VERSION 5.7 ;
  NOWIREEXTENSIONATPIN ON ;
  DIVIDERCHAR "/" ;
  BUSBITCHARS "[]" ;
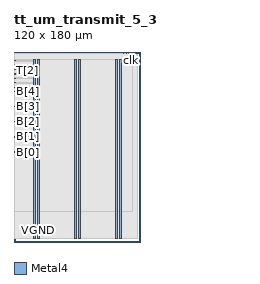
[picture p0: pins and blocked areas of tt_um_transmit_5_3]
MACRO tt_um_transmit_5_3
  CLASS BLOCK ;
  FOREIGN tt_um_transmit_5_3 ;
  ORIGIN 0.000 0.000 ;
  SIZE 120.000 BY 180.000 ;
  PIN B[0]
    DIRECTION OUTPUT ;
    USE SIGNAL ;
    ANTENNADIFFAREA 5.801400 ;
    PORT
      LAYER Metal4 ;
        RECT 0.000 85.100 1.000 85.400 ;
    END
  END B[0]
  PIN B[1]
    DIRECTION OUTPUT ;
    USE SIGNAL ;
    ANTENNADIFFAREA 1.601600 ;
    PORT
      LAYER Metal4 ;
        RECT 0.000 99.400 1.000 99.700 ;
    END
  END B[1]
  PIN B[2]
    DIRECTION OUTPUT ;
    USE SIGNAL ;
    ANTENNADIFFAREA 5.179600 ;
    PORT
      LAYER Metal4 ;
        RECT 0.000 113.700 1.000 114.000 ;
    END
  END B[2]
  PIN B[3]
    DIRECTION OUTPUT ;
    USE SIGNAL ;
    ANTENNADIFFAREA 2.243600 ;
    PORT
      LAYER Metal4 ;
        RECT 0.000 128.000 1.000 128.300 ;
    END
  END B[3]
  PIN B[4]
    DIRECTION OUTPUT ;
    USE SIGNAL ;
    ANTENNADIFFAREA 5.801400 ;
    PORT
      LAYER Metal4 ;
        RECT 0.000 142.300 1.000 142.600 ;
    END
  END B[4]
  PIN T[0]
    DIRECTION OUTPUT ;
    USE SIGNAL ;
    ANTENNADIFFAREA 1.055600 ;
    PORT
      LAYER Metal4 ;
        RECT 0.000 146.500 1.000 146.800 ;
    END
  END T[0]
  PIN T[1]
    DIRECTION OUTPUT ;
    USE SIGNAL ;
    ANTENNADIFFAREA 4.408000 ;
    PORT
      LAYER Metal4 ;
        RECT 0.000 150.700 1.000 151.000 ;
    END
  END T[1]
  PIN T[2]
    DIRECTION OUTPUT ;
    USE SIGNAL ;
    ANTENNADIFFAREA 4.731200 ;
    PORT
      LAYER Metal4 ;
        RECT 0.000 154.900 1.000 155.200 ;
    END
  END T[2]
  PIN T[3]
    DIRECTION OUTPUT ;
    USE SIGNAL ;
    ANTENNADIFFAREA 2.059200 ;
    PORT
      LAYER Metal4 ;
        RECT 0.000 159.100 1.000 159.400 ;
    END
  END T[3]
  PIN T[4]
    DIRECTION OUTPUT ;
    USE SIGNAL ;
    ANTENNAGATEAREA 5.072000 ;
    ANTENNADIFFAREA 3.240100 ;
    PORT
      LAYER Metal4 ;
        RECT 0.000 163.300 1.000 163.600 ;
    END
  END T[4]
  PIN T[5]
    DIRECTION OUTPUT ;
    USE SIGNAL ;
    ANTENNADIFFAREA 4.731200 ;
    PORT
      LAYER Metal4 ;
        RECT 0.000 167.500 1.000 167.800 ;
    END
  END T[5]
  PIN T[6]
    DIRECTION OUTPUT ;
    USE SIGNAL ;
    ANTENNADIFFAREA 4.408000 ;
    PORT
      LAYER Metal4 ;
        RECT 0.000 171.700 1.000 172.000 ;
    END
  END T[6]
  PIN VGND
    DIRECTION INOUT ;
    USE GROUND ;
    PORT
      LAYER Metal4 ;
        RECT 22.180 3.620 23.780 172.780 ;
    END
    PORT
      LAYER Metal4 ;
        RECT 61.050 3.620 62.650 172.780 ;
    END
    PORT
      LAYER Metal4 ;
        RECT 99.920 3.620 101.520 172.780 ;
    END
  END VGND
  PIN VPWR
    DIRECTION INOUT ;
    USE POWER ;
    PORT
      LAYER Metal4 ;
        RECT 18.880 3.620 20.480 172.780 ;
    END
    PORT
      LAYER Metal4 ;
        RECT 57.750 3.620 59.350 172.780 ;
    END
    PORT
      LAYER Metal4 ;
        RECT 96.620 3.620 98.220 172.780 ;
    END
  END VPWR
  PIN clk
    DIRECTION INPUT ;
    USE SIGNAL ;
    ANTENNAGATEAREA 4.738000 ;
    PORT
      LAYER Metal4 ;
        RECT 111.700 179.000 112.000 180.000 ;
    END
  END clk
  PIN enable
    DIRECTION INPUT ;
    USE SIGNAL ;
    ANTENNAGATEAREA 0.396000 ;
    PORT
      LAYER Metal4 ;
        RECT 103.420 179.000 103.720 180.000 ;
    END
  END enable
  PIN in
    DIRECTION INPUT ;
    USE SIGNAL ;
    ANTENNAGATEAREA 0.396000 ;
    PORT
      LAYER Metal4 ;
        RECT 106.180 179.000 106.480 180.000 ;
    END
  END in
  PIN rst_n
    DIRECTION INPUT ;
    USE SIGNAL ;
    ANTENNAGATEAREA 0.396000 ;
    PORT
      LAYER Metal4 ;
        RECT 108.940 179.000 109.240 180.000 ;
    END
  END rst_n
  OBS
      LAYER Nwell ;
        RECT 2.930 3.490 116.910 172.910 ;
      LAYER Metal1 ;
        RECT 3.360 3.620 116.480 172.780 ;
      LAYER Metal2 ;
        RECT 2.380 3.730 116.900 177.430 ;
      LAYER Metal3 ;
        RECT 0.090 3.780 116.950 177.380 ;
      LAYER Metal4 ;
        RECT 0.140 178.700 103.120 179.000 ;
        RECT 104.020 178.700 105.880 179.000 ;
        RECT 106.780 178.700 108.640 179.000 ;
        RECT 109.540 178.700 111.400 179.000 ;
        RECT 0.140 173.080 111.990 178.700 ;
        RECT 0.140 172.300 18.580 173.080 ;
        RECT 1.300 171.400 18.580 172.300 ;
        RECT 0.140 168.100 18.580 171.400 ;
        RECT 1.300 167.200 18.580 168.100 ;
        RECT 0.140 163.900 18.580 167.200 ;
        RECT 1.300 163.000 18.580 163.900 ;
        RECT 0.140 159.700 18.580 163.000 ;
        RECT 1.300 158.800 18.580 159.700 ;
        RECT 0.140 155.500 18.580 158.800 ;
        RECT 1.300 154.600 18.580 155.500 ;
        RECT 0.140 151.300 18.580 154.600 ;
        RECT 1.300 150.400 18.580 151.300 ;
        RECT 0.140 147.100 18.580 150.400 ;
        RECT 1.300 146.200 18.580 147.100 ;
        RECT 0.140 142.900 18.580 146.200 ;
        RECT 1.300 142.000 18.580 142.900 ;
        RECT 0.140 128.600 18.580 142.000 ;
        RECT 1.300 127.700 18.580 128.600 ;
        RECT 0.140 114.300 18.580 127.700 ;
        RECT 1.300 113.400 18.580 114.300 ;
        RECT 0.140 100.000 18.580 113.400 ;
        RECT 1.300 99.100 18.580 100.000 ;
        RECT 0.140 85.700 18.580 99.100 ;
        RECT 1.300 84.800 18.580 85.700 ;
        RECT 0.140 29.210 18.580 84.800 ;
        RECT 20.780 29.210 21.880 173.080 ;
        RECT 24.080 29.210 57.450 173.080 ;
        RECT 59.650 29.210 60.750 173.080 ;
        RECT 62.950 29.210 96.320 173.080 ;
        RECT 98.520 29.210 99.620 173.080 ;
        RECT 101.820 29.210 111.990 173.080 ;
  END
END tt_um_transmit_5_3
END LIBRARY

